VERSION 5.8 ;
BUSBITCHARS "<>" ;
DIVIDERCHAR "/" ;

LAYER M1
   TYPE ROUTING ;
   WIDTH 1 ;
   PITCH 2 ;
   DIRECTION HORIZONTAL ;
END M1

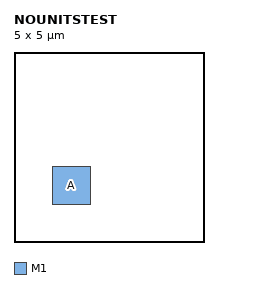
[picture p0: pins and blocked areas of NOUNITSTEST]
MACRO NOUNITSTEST
   CLASS CORE ;
   SIZE 5 BY 5 ;

   PIN A
      DIRECTION INPUT ;
      PORT
         LAYER M1 ;
         RECT 1 1 2 2 ;
      END
   END A
END NOUNITSTEST
